VERSION 5.7 ;
  NOWIREEXTENSIONATPIN ON ;
  DIVIDERCHAR "/" ;
  BUSBITCHARS "[]" ;
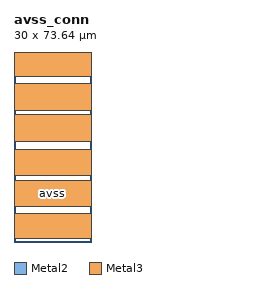
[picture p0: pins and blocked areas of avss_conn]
MACRO avss_conn
  CLASS BLOCK ;
  FOREIGN avss_conn ;
  ORIGIN 0.000 0.000 ;
  SIZE 30.000 BY 73.640 ;
  PIN avss
    DIRECTION INOUT ;
    USE GROUND ;
    PORT
      LAYER Metal2 ;
        RECT 0.000 1.360 30.000 10.860 ;
        RECT 0.000 13.760 30.000 24.010 ;
        RECT 0.000 25.610 30.000 35.860 ;
        RECT 0.000 39.140 30.000 49.390 ;
        RECT 0.000 50.990 30.000 61.240 ;
        RECT 0.000 64.140 30.000 73.640 ;
      LAYER Metal3 ;
        RECT 0.000 1.360 30.000 10.860 ;
        RECT 0.000 13.760 30.000 24.010 ;
        RECT 0.000 25.610 30.000 35.860 ;
        RECT 0.000 39.140 30.000 49.390 ;
        RECT 0.000 50.990 30.000 61.240 ;
        RECT 0.000 64.140 30.000 73.640 ;
    END
  END avss
END avss_conn
END LIBRARY
